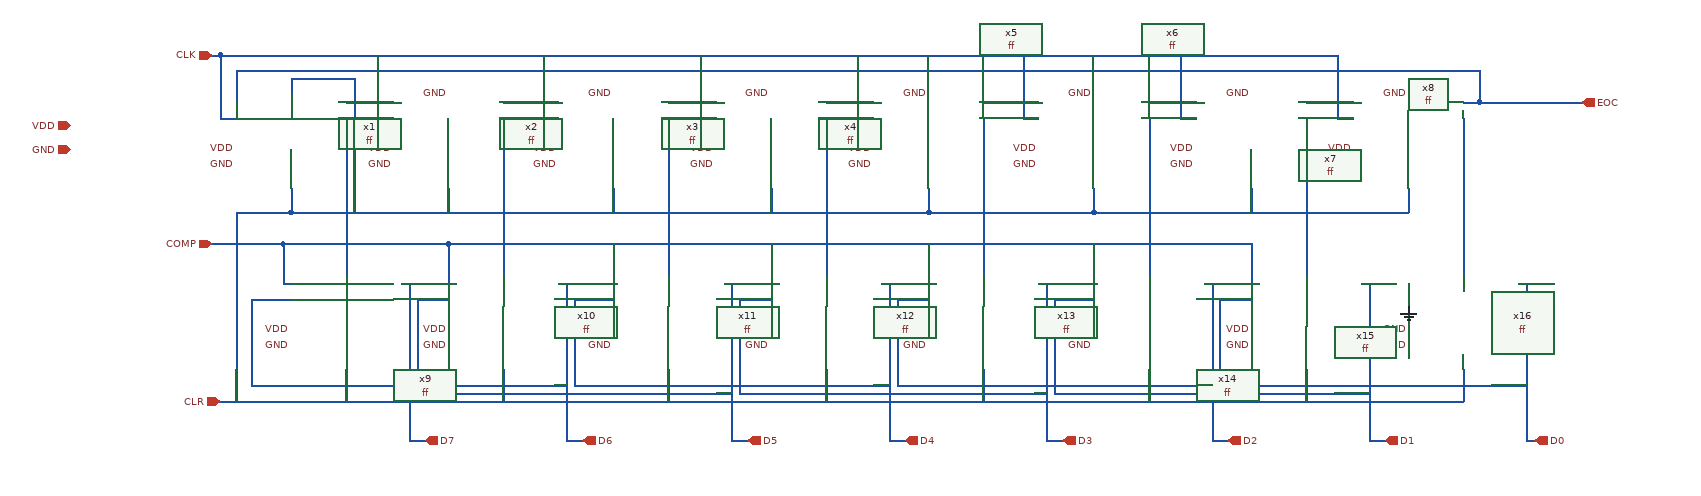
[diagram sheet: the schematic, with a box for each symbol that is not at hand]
v {xschem version=3.4.5 file_version=1.2
}
G {}
K {}
V {}
S {}
E {}
N -100 -260 -40 -260 {
lab=#net1}
N 100 -260 160 -260 {
lab=#net2}
N 160 -260 170 -260 {
lab=#net2}
N 310 -260 370 -260 {
lab=#net3}
N 510 -260 570 -260 {
lab=#net4}
N 710 -260 780 -260 {
lab=#net5}
N 920 -260 980 -260 {
lab=#net6}
N 1120 -260 1180 -260 {
lab=#net7}
N -100 -240 -100 -60 {
lab=#net8}
N 100 -230 100 -60 {
lab=#net9}
N 310 -240 310 -60 {
lab=#net10}
N 510 -240 510 -60 {
lab=#net11}
N 710 -240 710 -60 {
lab=#net12}
N 920 -240 920 -60 {
lab=#net13}
N 1120 -240 1120 -60 {
lab=#net14}
N 1320 -240 1320 -60 {
lab=#net15}
N -180 -30 -170 -30 {
lab=COMP}
N -180 -80 -180 -30 {
lab=COMP}
N -230 -80 -180 -80 {
lab=COMP}
N -180 -80 -30 -80 {
lab=COMP}
N -30 -80 30 -80 {
lab=COMP}
N 30 -80 30 -30 {
lab=COMP}
N 1050 -80 1050 -30 {
lab=COMP}
N 850 -80 850 -30 {
lab=COMP}
N 640 -80 640 -30 {
lab=COMP}
N 440 -80 440 -30 {
lab=COMP}
N 240 -80 240 -30 {
lab=COMP}
N -260 120 1320 120 {
lab=CLR}
N 1320 80 1320 120 {
lab=CLR}
N 1120 80 1120 120 {
lab=CLR}
N 920 80 920 120 {
lab=CLR}
N 710 80 710 120 {
lab=CLR}
N 510 80 510 120 {
lab=CLR}
N 310 80 310 120 {
lab=CLR}
N 100 80 100 120 {
lab=CLR}
N -100 80 -100 120 {
lab=CLR}
N -170 -290 -170 -270 {
lab=CLR}
N -240 -120 -240 120 {
lab=CLR}
N -240 -120 -170 -120 {
lab=CLR}
N -170 -150 -170 -120 {
lab=CLR}
N -170 -120 640 -120 {
lab=CLR}
N 640 -150 640 -120 {
lab=CLR}
N 640 -120 850 -120 {
lab=CLR}
N 850 -150 850 -120 {
lab=CLR}
N 850 -120 1250 -120 {
lab=CLR}
N 1250 -150 1250 -120 {
lab=CLR}
N 1050 -150 1050 -120 {
lab=CLR}
N 440 -150 440 -120 {
lab=CLR}
N 240 -150 240 -120 {
lab=CLR}
N 30 -150 30 -120 {
lab=CLR}
N -270 -80 -230 -80 {
lab=COMP}
N -90 -290 -90 -120 {
lab=CLR}
N -170 -290 -90 -290 {
lab=CLR}
N 1320 -260 1340 -260 {
lab=EOC}
N 1340 -300 1340 -260 {
lab=EOC}
N -240 -300 1340 -300 {
lab=EOC}
N -240 -300 -240 -260 {
lab=EOC}
N -270 -320 -260 -320 {
lab=CLK}
N -260 -320 -260 -240 {
lab=CLK}
N -260 -240 -240 -240 {
lab=CLK}
N -260 -320 1160 -320 {
lab=CLK}
N 1160 -320 1160 -240 {
lab=CLK}
N 1160 -240 1180 -240 {
lab=CLK}
N 960 -240 980 -240 {
lab=CLK}
N 960 -320 960 -240 {
lab=CLK}
N 760 -240 780 -240 {
lab=CLK}
N 760 -320 760 -240 {
lab=CLK}
N 550 -240 570 -240 {
lab=CLK}
N 550 -320 550 -240 {
lab=CLK}
N 350 -240 370 -240 {
lab=CLK}
N 350 -320 350 -240 {
lab=CLK}
N 150 -240 170 -240 {
lab=CLK}
N 150 -320 150 -240 {
lab=CLK}
N -60 -240 -40 -240 {
lab=CLK}
N -60 -320 -60 -240 {
lab=CLK}
N -100 -60 -100 -40 {
lab=#net8}
N 100 -60 100 -40 {
lab=#net9}
N 310 -60 310 -40 {
lab=#net10}
N 510 -60 510 -40 {
lab=#net11}
N 710 -60 710 -40 {
lab=#net12}
N 920 -60 920 -40 {
lab=#net13}
N 1120 -60 1120 -40 {
lab=#net14}
N 1320 -60 1320 -40 {
lab=#net15}
N -30 -30 -20 -30 {
lab=D7}
N -20 -30 -20 160 {
lab=D7}
N 170 -30 180 -30 {
lab=D6}
N 180 -30 180 160 {
lab=D6}
N 380 -30 390 -30 {
lab=D5}
N 390 -30 390 160 {
lab=D5}
N 580 -30 590 -30 {
lab=D4}
N 590 -30 590 160 {
lab=D4}
N 780 -30 790 -30 {
lab=D3}
N 790 -30 790 160 {
lab=D3}
N 990 -30 1000 -30 {
lab=D2}
N 1000 -30 1000 160 {
lab=D2}
N 1190 -30 1200 -30 {
lab=D1}
N 1200 -30 1200 160 {
lab=D1}
N 1390 -30 1400 -30 {
lab=D0}
N 1400 -30 1400 160 {
lab=D0}
N -220 -10 -170 -10 {
lab=D6}
N -220 -10 -220 100 {
lab=D6}
N -220 100 180 100 {
lab=D6}
N -10 -10 30 -10 {
lab=D5}
N -10 -10 -10 90 {
lab=D5}
N -10 90 -10 110 {
lab=D5}
N -10 110 390 110 {
lab=D5}
N 190 -10 240 -10 {
lab=D4}
N 190 -10 190 100 {
lab=D4}
N 190 100 590 100 {
lab=D4}
N 400 -10 440 -10 {
lab=D3}
N 400 -10 400 110 {
lab=D3}
N 400 110 790 110 {
lab=D3}
N 600 -10 640 -10 {
lab=D2}
N 600 -10 600 100 {
lab=D2}
N 600 100 1000 100 {
lab=D2}
N 800 -10 850 -10 {
lab=D1}
N 800 -10 800 110 {
lab=D1}
N 800 110 1200 110 {
lab=D1}
N 1010 -10 1050 -10 {
lab=D0}
N 1010 -10 1010 100 {
lab=D0}
N 1010 100 1400 100 {
lab=D0}
N 30 -80 1050 -80 {
lab=COMP}
N 1250 -30 1250 -0 {
lab=GND}
N 1340 -260 1470 -260 {
lab=EOC}
N 1400 160 1400 170 {
lab=D0}
N 1400 170 1410 170 {
lab=D0}
N -20 160 -20 170 {
lab=D7}
N -20 170 0 170 {
lab=D7}
N 180 160 180 170 {
lab=D6}
N 180 170 200 170 {
lab=D6}
N 390 160 390 170 {
lab=D5}
N 390 170 410 170 {
lab=D5}
N 590 160 590 170 {
lab=D4}
N 590 170 610 170 {
lab=D4}
N 790 160 790 170 {
lab=D3}
N 790 170 810 170 {
lab=D3}
N 1000 160 1000 170 {
lab=D2}
N 1000 170 1020 170 {
lab=D2}
N 1200 160 1200 170 {
lab=D1}
N 1200 170 1220 170 {
lab=D1}
N 100 -240 100 -230 {
lab=#net9}
C {devices/ipin.sym} -450 -230 0 0 {name=p2 lab=VDD}
C {devices/ipin.sym} -450 -200 0 0 {name=p3 lab=GND
}
C {devices/ipin.sym} -270 -320 0 0 {name=p1 lab=CLK
}
C {devices/lab_pin.sym} -240 -200 0 0 {name=p4 sig_type=std_logic lab=VDD}
C {devices/lab_pin.sym} -40 -200 0 0 {name=p5 sig_type=std_logic lab=VDD}
C {devices/lab_pin.sym} 170 -200 0 0 {name=p6 sig_type=std_logic lab=VDD}
C {devices/lab_pin.sym} 370 -200 0 0 {name=p7 sig_type=std_logic lab=VDD}
C {devices/lab_pin.sym} 570 -200 0 0 {name=p8 sig_type=std_logic lab=VDD}
C {devices/lab_pin.sym} 780 -200 0 0 {name=p9 sig_type=std_logic lab=VDD}
C {devices/lab_pin.sym} 980 -200 0 0 {name=p10 sig_type=std_logic lab=VDD}
C {devices/lab_pin.sym} 1180 -200 0 0 {name=p11 sig_type=std_logic lab=VDD}
C {devices/lab_pin.sym} -240 -180 0 0 {name=p20 sig_type=std_logic lab=GND}
C {devices/lab_pin.sym} -40 -180 0 0 {name=p21 sig_type=std_logic lab=GND}
C {devices/lab_pin.sym} 170 -180 0 0 {name=p22 sig_type=std_logic lab=GND}
C {devices/lab_pin.sym} 370 -180 0 0 {name=p23 sig_type=std_logic lab=GND}
C {devices/lab_pin.sym} 570 -180 0 0 {name=p24 sig_type=std_logic lab=GND}
C {devices/lab_pin.sym} 780 -180 0 0 {name=p25 sig_type=std_logic lab=GND}
C {devices/lab_pin.sym} 980 -180 0 0 {name=p26 sig_type=std_logic lab=GND}
C {devices/lab_pin.sym} 1180 -180 0 0 {name=p27 sig_type=std_logic lab=GND}
C {devices/lab_pin.sym} -170 30 0 0 {name=p12 sig_type=std_logic lab=VDD}
C {devices/lab_pin.sym} 30 30 0 0 {name=p13 sig_type=std_logic lab=VDD}
C {devices/lab_pin.sym} 240 30 0 0 {name=p14 sig_type=std_logic lab=VDD}
C {devices/lab_pin.sym} 440 30 0 0 {name=p15 sig_type=std_logic lab=VDD}
C {devices/lab_pin.sym} 640 30 0 0 {name=p16 sig_type=std_logic lab=VDD}
C {devices/lab_pin.sym} 850 30 0 0 {name=p17 sig_type=std_logic lab=VDD}
C {devices/lab_pin.sym} 1050 30 0 0 {name=p18 sig_type=std_logic lab=VDD}
C {devices/lab_pin.sym} 1250 50 0 0 {name=p19 sig_type=std_logic lab=VDD}
C {devices/lab_pin.sym} -170 50 0 0 {name=p28 sig_type=std_logic lab=GND}
C {devices/lab_pin.sym} 30 50 0 0 {name=p29 sig_type=std_logic lab=GND}
C {devices/lab_pin.sym} 240 50 0 0 {name=p30 sig_type=std_logic lab=GND}
C {devices/lab_pin.sym} 440 50 0 0 {name=p31 sig_type=std_logic lab=GND}
C {devices/lab_pin.sym} 640 50 0 0 {name=p32 sig_type=std_logic lab=GND}
C {devices/lab_pin.sym} 850 50 0 0 {name=p33 sig_type=std_logic lab=GND}
C {devices/lab_pin.sym} 1050 50 0 0 {name=p34 sig_type=std_logic lab=GND}
C {devices/lab_pin.sym} 1250 30 0 0 {name=p35 sig_type=std_logic lab=GND}
C {devices/ipin.sym} -260 120 0 0 {name=p36 lab=CLR
}
C {devices/ipin.sym} -270 -80 0 0 {name=p45 lab=COMP
}
C {ff.sym} -90 -210 0 0 {name=x1}
C {ff.sym} 110 -210 0 0 {name=x2}
C {ff.sym} 320 -210 0 0 {name=x3}
C {ff.sym} 520 -210 0 0 {name=x4}
C {ff.sym} 720 -210 0 0 {name=x5}
C {ff.sym} 930 -210 0 0 {name=x6}
C {ff.sym} 1130 -210 0 0 {name=x7}
C {ff.sym} 1330 -210 0 0 {name=x8}
C {ff.sym} -20 20 0 0 {name=x9}
C {ff.sym} 180 20 0 0 {name=x10}
C {ff.sym} 390 20 0 0 {name=x11}
C {ff.sym} 590 20 0 0 {name=x12}
C {ff.sym} 790 20 0 0 {name=x13}
C {ff.sym} 1000 20 0 0 {name=x14}
C {ff.sym} 1200 20 0 0 {name=x15}
C {ff.sym} 1400 20 0 0 {name=x16}
C {devices/gnd.sym} 1250 0 0 0 {name=l1 lab=GND}
C {devices/opin.sym} 1410 170 0 0 {name=p37 lab=D0}
C {devices/opin.sym} 1470 -260 0 0 {name=p38 lab=EOC}
C {devices/opin.sym} 1220 170 0 0 {name=p39 lab=D1}
C {devices/opin.sym} 1020 170 0 0 {name=p40 lab=D2}
C {devices/opin.sym} 810 170 0 0 {name=p41 lab=D3}
C {devices/opin.sym} 610 170 0 0 {name=p42 lab=D4}
C {devices/opin.sym} 410 170 0 0 {name=p43 lab=D5}
C {devices/opin.sym} 200 170 0 0 {name=p44 lab=D6}
C {devices/opin.sym} 0 170 0 0 {name=p46 lab=D7}
C {devices/lab_pin.sym} 30 -270 1 0 {name=p47 sig_type=std_logic lab=GND}
C {devices/lab_pin.sym} 240 -270 1 0 {name=p48 sig_type=std_logic lab=GND}
C {devices/lab_pin.sym} 440 -270 1 0 {name=p49 sig_type=std_logic lab=GND}
C {devices/lab_pin.sym} 640 -270 1 0 {name=p50 sig_type=std_logic lab=GND}
C {devices/lab_pin.sym} 850 -270 1 0 {name=p51 sig_type=std_logic lab=GND}
C {devices/lab_pin.sym} 1050 -270 1 0 {name=p52 sig_type=std_logic lab=GND}
C {devices/lab_pin.sym} 1250 -270 1 0 {name=p53 sig_type=std_logic lab=GND}
